VERSION 5.4 ;
NAMESCASESENSITIVE ON ;
BUSBITCHARS "[]" ;
DIVIDERCHAR "/" ;
UNITS
  DATABASE MICRONS 2000 ;
END UNITS
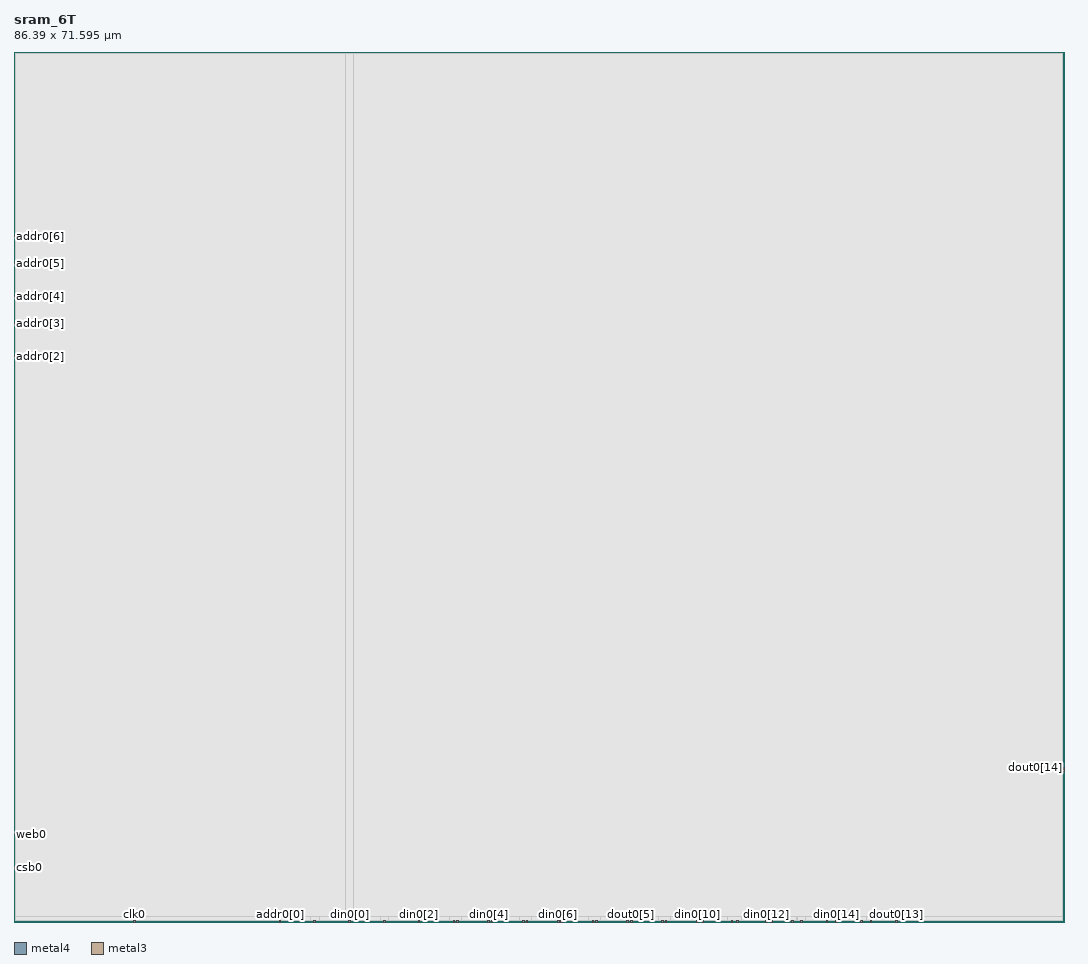
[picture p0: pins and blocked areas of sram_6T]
MACRO sram_6T
   CLASS BLOCK ;
   SIZE 86.39 BY 71.595 ;
   SYMMETRY X Y R90 ;
   PIN din0[0]
      DIRECTION INPUT ;
      PORT
         LAYER metal4 ;
         RECT  27.5425 0.0 27.6825 0.14 ;
      END
   END din0[0]
   PIN din0[1]
      DIRECTION INPUT ;
      PORT
         LAYER metal4 ;
         RECT  30.4025 0.0 30.5425 0.14 ;
      END
   END din0[1]
   PIN din0[2]
      DIRECTION INPUT ;
      PORT
         LAYER metal4 ;
         RECT  33.2625 0.0 33.4025 0.14 ;
      END
   END din0[2]
   PIN din0[3]
      DIRECTION INPUT ;
      PORT
         LAYER metal4 ;
         RECT  36.1225 0.0 36.2625 0.14 ;
      END
   END din0[3]
   PIN din0[4]
      DIRECTION INPUT ;
      PORT
         LAYER metal4 ;
         RECT  38.9825 0.0 39.1225 0.14 ;
      END
   END din0[4]
   PIN din0[5]
      DIRECTION INPUT ;
      PORT
         LAYER metal4 ;
         RECT  41.8425 0.0 41.9825 0.14 ;
      END
   END din0[5]
   PIN din0[6]
      DIRECTION INPUT ;
      PORT
         LAYER metal4 ;
         RECT  44.7025 0.0 44.8425 0.14 ;
      END
   END din0[6]
   PIN din0[7]
      DIRECTION INPUT ;
      PORT
         LAYER metal4 ;
         RECT  47.5625 0.0 47.7025 0.14 ;
      END
   END din0[7]
   PIN din0[8]
      DIRECTION INPUT ;
      PORT
         LAYER metal4 ;
         RECT  50.4225 0.0 50.5625 0.14 ;
      END
   END din0[8]
   PIN din0[9]
      DIRECTION INPUT ;
      PORT
         LAYER metal4 ;
         RECT  53.2825 0.0 53.4225 0.14 ;
      END
   END din0[9]
   PIN din0[10]
      DIRECTION INPUT ;
      PORT
         LAYER metal4 ;
         RECT  56.1425 0.0 56.2825 0.14 ;
      END
   END din0[10]
   PIN din0[11]
      DIRECTION INPUT ;
      PORT
         LAYER metal4 ;
         RECT  59.0025 0.0 59.1425 0.14 ;
      END
   END din0[11]
   PIN din0[12]
      DIRECTION INPUT ;
      PORT
         LAYER metal4 ;
         RECT  61.8625 0.0 62.0025 0.14 ;
      END
   END din0[12]
   PIN din0[13]
      DIRECTION INPUT ;
      PORT
         LAYER metal4 ;
         RECT  64.7225 0.0 64.8625 0.14 ;
      END
   END din0[13]
   PIN din0[14]
      DIRECTION INPUT ;
      PORT
         LAYER metal4 ;
         RECT  67.5825 0.0 67.7225 0.14 ;
      END
   END din0[14]
   PIN din0[15]
      DIRECTION INPUT ;
      PORT
         LAYER metal4 ;
         RECT  70.4425 0.0 70.5825 0.14 ;
      END
   END din0[15]
   PIN addr0[0]
      DIRECTION INPUT ;
      PORT
         LAYER metal4 ;
         RECT  21.8225 0.0 21.9625 0.14 ;
      END
   END addr0[0]
   PIN addr0[1]
      DIRECTION INPUT ;
      PORT
         LAYER metal4 ;
         RECT  24.6825 0.0 24.8225 0.14 ;
      END
   END addr0[1]
   PIN addr0[2]
      DIRECTION INPUT ;
      PORT
         LAYER metal3 ;
         RECT  0.0 46.43 0.14 46.57 ;
      END
   END addr0[2]
   PIN addr0[3]
      DIRECTION INPUT ;
      PORT
         LAYER metal3 ;
         RECT  0.0 49.16 0.14 49.3 ;
      END
   END addr0[3]
   PIN addr0[4]
      DIRECTION INPUT ;
      PORT
         LAYER metal3 ;
         RECT  0.0 51.37 0.14 51.51 ;
      END
   END addr0[4]
   PIN addr0[5]
      DIRECTION INPUT ;
      PORT
         LAYER metal3 ;
         RECT  0.0 54.1 0.14 54.24 ;
      END
   END addr0[5]
   PIN addr0[6]
      DIRECTION INPUT ;
      PORT
         LAYER metal3 ;
         RECT  0.0 56.31 0.14 56.45 ;
      END
   END addr0[6]
   PIN csb0
      DIRECTION INPUT ;
      PORT
         LAYER metal3 ;
         RECT  0.0 4.44 0.14 4.58 ;
      END
   END csb0
   PIN web0
      DIRECTION INPUT ;
      PORT
         LAYER metal3 ;
         RECT  0.0 7.17 0.14 7.31 ;
      END
   END web0
   PIN clk0
      DIRECTION INPUT ;
      PORT
         LAYER metal4 ;
         RECT  9.84 0.0 9.98 0.14 ;
      END
   END clk0
   PIN dout0[0]
      DIRECTION OUTPUT ;
      PORT
         LAYER metal4 ;
         RECT  36.4075 0.0 36.5475 0.14 ;
      END
   END dout0[0]
   PIN dout0[1]
      DIRECTION OUTPUT ;
      PORT
         LAYER metal4 ;
         RECT  39.2675 0.0 39.4075 0.14 ;
      END
   END dout0[1]
   PIN dout0[2]
      DIRECTION OUTPUT ;
      PORT
         LAYER metal4 ;
         RECT  42.1275 0.0 42.2675 0.14 ;
      END
   END dout0[2]
   PIN dout0[3]
      DIRECTION OUTPUT ;
      PORT
         LAYER metal4 ;
         RECT  44.9875 0.0 45.1275 0.14 ;
      END
   END dout0[3]
   PIN dout0[4]
      DIRECTION OUTPUT ;
      PORT
         LAYER metal4 ;
         RECT  47.8475 0.0 47.9875 0.14 ;
      END
   END dout0[4]
   PIN dout0[5]
      DIRECTION OUTPUT ;
      PORT
         LAYER metal4 ;
         RECT  50.7075 0.0 50.8475 0.14 ;
      END
   END dout0[5]
   PIN dout0[6]
      DIRECTION OUTPUT ;
      PORT
         LAYER metal4 ;
         RECT  53.5675 0.0 53.7075 0.14 ;
      END
   END dout0[6]
   PIN dout0[7]
      DIRECTION OUTPUT ;
      PORT
         LAYER metal4 ;
         RECT  56.625 0.0 56.765 0.14 ;
      END
   END dout0[7]
   PIN dout0[8]
      DIRECTION OUTPUT ;
      PORT
         LAYER metal4 ;
         RECT  59.445 0.0 59.585 0.14 ;
      END
   END dout0[8]
   PIN dout0[9]
      DIRECTION OUTPUT ;
      PORT
         LAYER metal4 ;
         RECT  62.265 0.0 62.405 0.14 ;
      END
   END dout0[9]
   PIN dout0[10]
      DIRECTION OUTPUT ;
      PORT
         LAYER metal4 ;
         RECT  63.965 0.0 64.105 0.14 ;
      END
   END dout0[10]
   PIN dout0[11]
      DIRECTION OUTPUT ;
      PORT
         LAYER metal4 ;
         RECT  66.825 0.0 66.965 0.14 ;
      END
   END dout0[11]
   PIN dout0[12]
      DIRECTION OUTPUT ;
      PORT
         LAYER metal4 ;
         RECT  69.685 0.0 69.825 0.14 ;
      END
   END dout0[12]
   PIN dout0[13]
      DIRECTION OUTPUT ;
      PORT
         LAYER metal4 ;
         RECT  72.545 0.0 72.685 0.14 ;
      END
   END dout0[13]
   PIN dout0[14]
      DIRECTION OUTPUT ;
      PORT
         LAYER metal3 ;
         RECT  86.25 12.6025 86.39 12.7425 ;
      END
   END dout0[14]
   PIN dout0[15]
      DIRECTION OUTPUT ;
      PORT
         LAYER metal3 ;
         RECT  86.25 12.3675 86.39 12.5075 ;
      END
   END dout0[15]
   PIN vdd
      DIRECTION INOUT ;
      USE POWER ; 
      SHAPE ABUTMENT ; 
      PORT
      END
   END vdd
   PIN gnd
      DIRECTION INOUT ;
      USE GROUND ; 
      SHAPE ABUTMENT ; 
      PORT
      END
   END gnd
   OBS
   LAYER  metal1 ;
      RECT  0.14 0.14 86.25 71.455 ;
   LAYER  metal2 ;
      RECT  0.14 0.14 86.25 71.455 ;
   LAYER  metal3 ;
      RECT  0.28 46.29 86.25 46.71 ;
      RECT  0.28 46.71 86.25 71.455 ;
      RECT  0.14 46.71 0.28 49.02 ;
      RECT  0.14 49.44 0.28 51.23 ;
      RECT  0.14 51.65 0.28 53.96 ;
      RECT  0.14 54.38 0.28 56.17 ;
      RECT  0.14 56.59 0.28 71.455 ;
      RECT  0.14 0.14 0.28 4.3 ;
      RECT  0.14 4.72 0.28 7.03 ;
      RECT  0.14 7.45 0.28 46.29 ;
      RECT  0.28 0.14 86.11 12.4625 ;
      RECT  0.28 12.4625 86.11 12.8825 ;
      RECT  0.28 12.8825 86.11 46.29 ;
      RECT  86.11 12.8825 86.25 46.29 ;
      RECT  86.11 0.14 86.25 12.2275 ;
   LAYER  metal4 ;
      RECT  0.14 0.42 27.2625 71.455 ;
      RECT  27.2625 0.42 27.9625 71.455 ;
      RECT  27.9625 0.42 86.25 71.455 ;
      RECT  27.9625 0.14 30.1225 0.42 ;
      RECT  30.8225 0.14 32.9825 0.42 ;
      RECT  33.6825 0.14 35.8425 0.42 ;
      RECT  22.2425 0.14 24.4025 0.42 ;
      RECT  25.1025 0.14 27.2625 0.42 ;
      RECT  0.14 0.14 9.56 0.42 ;
      RECT  10.26 0.14 21.5425 0.42 ;
      RECT  36.8275 0.14 38.7025 0.42 ;
      RECT  39.6875 0.14 41.5625 0.42 ;
      RECT  42.5475 0.14 44.4225 0.42 ;
      RECT  45.4075 0.14 47.2825 0.42 ;
      RECT  48.2675 0.14 50.1425 0.42 ;
      RECT  51.1275 0.14 53.0025 0.42 ;
      RECT  53.9875 0.14 55.8625 0.42 ;
      RECT  57.045 0.14 58.7225 0.42 ;
      RECT  59.865 0.14 61.5825 0.42 ;
      RECT  62.685 0.14 63.685 0.42 ;
      RECT  64.385 0.14 64.4425 0.42 ;
      RECT  65.1425 0.14 66.545 0.42 ;
      RECT  67.245 0.14 67.3025 0.42 ;
      RECT  68.0025 0.14 69.405 0.42 ;
      RECT  70.105 0.14 70.1625 0.42 ;
      RECT  70.8625 0.14 72.265 0.42 ;
      RECT  72.965 0.14 86.25 0.42 ;
   END
END    sram_6T
END    LIBRARY
